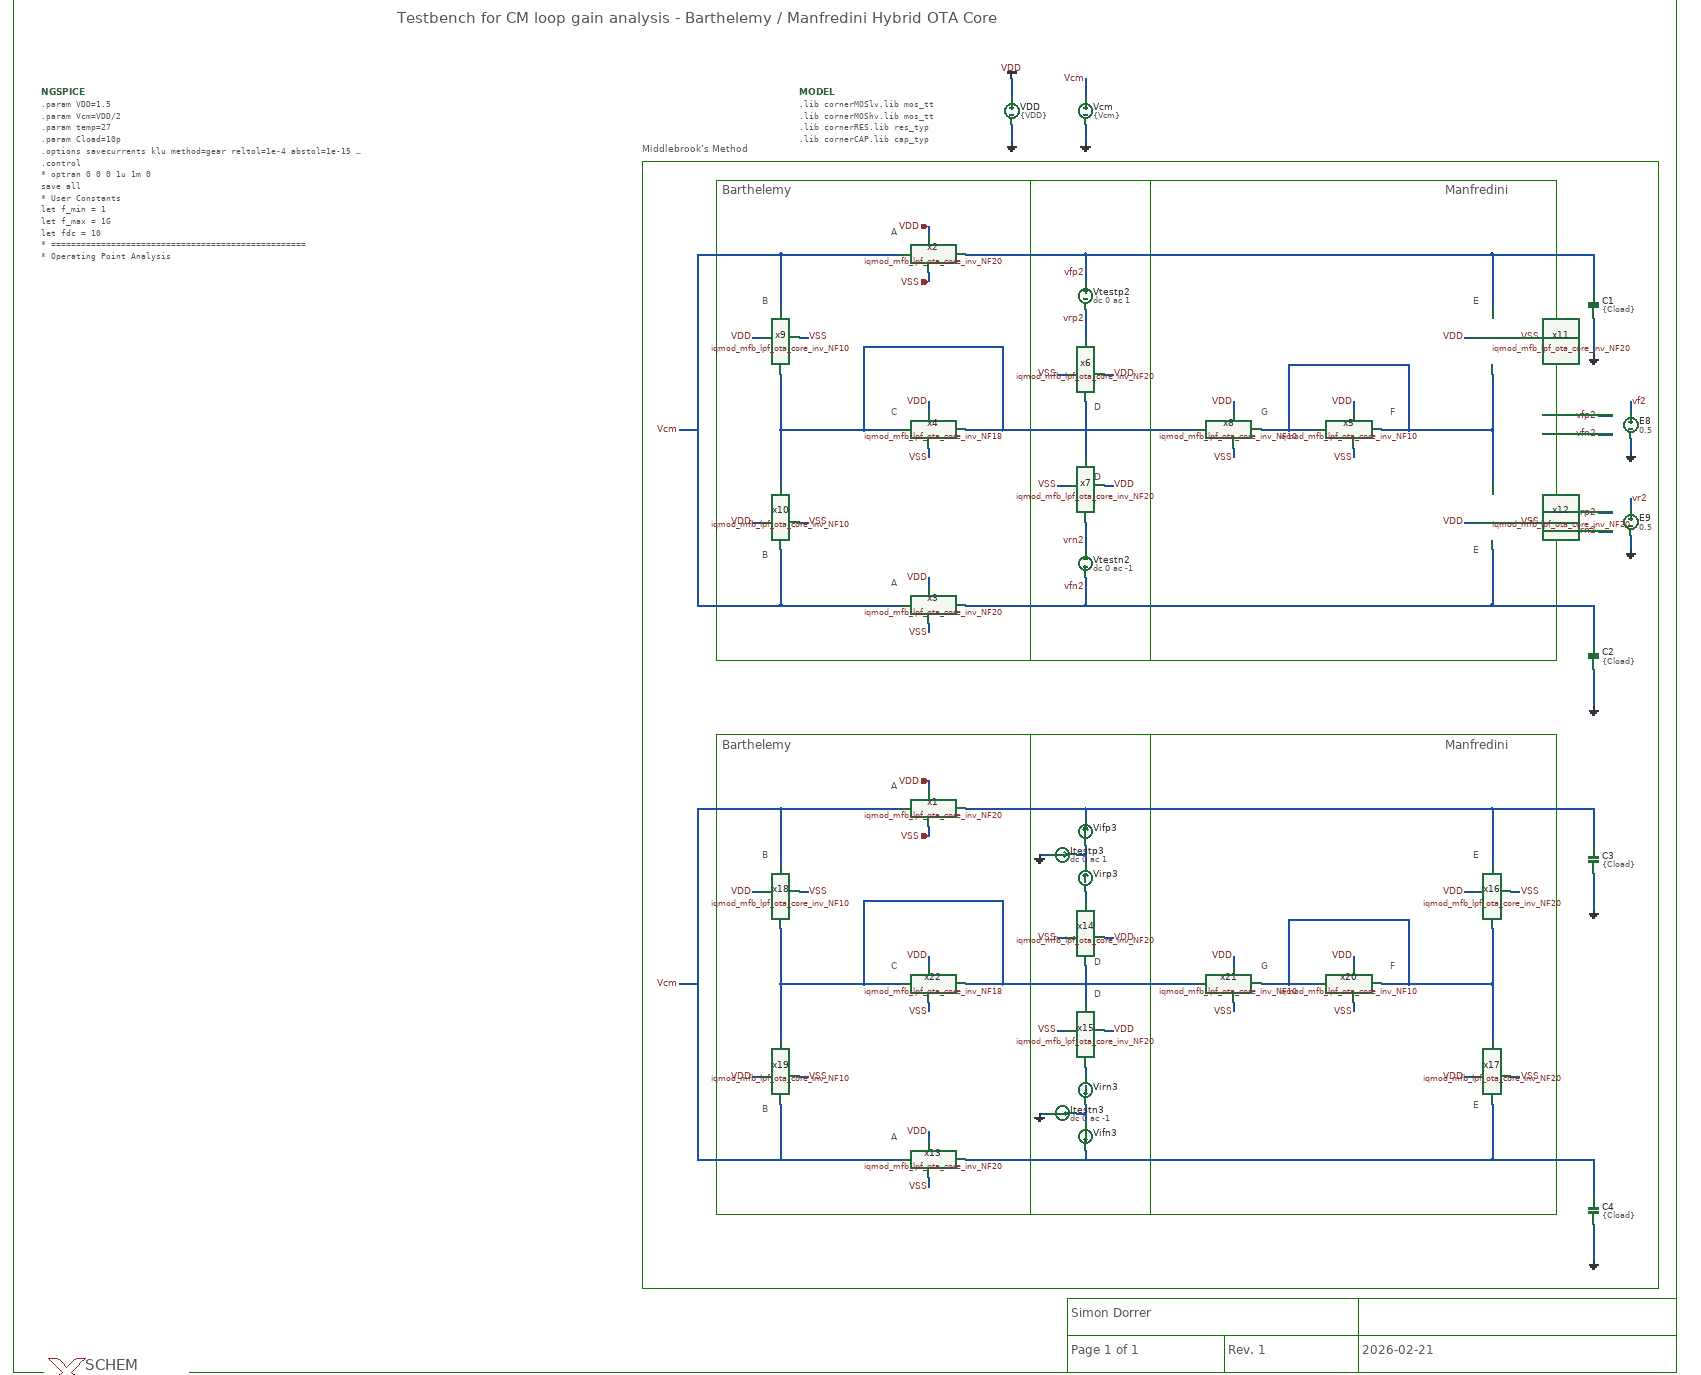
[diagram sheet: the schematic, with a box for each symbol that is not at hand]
v {xschem version=3.4.8RC file_version=1.3}
G {}
K {}
V {}
S {}
F {}
E {}
L 4 0 0 65 0 {}
L 4 2280 -160 2280 0 {}
L 4 2280 -160 3600 -160 {}
L 4 2280 -80 3600 -80 {}
L 4 2910 -80 2910 0 {}
L 4 2910 -160 2910 -80 {}
L 4 2620 -80 2620 0 {}
L 4 380 0 1000 0 {}
L 4 0 -2980 -0 -0 {}
L 4 3600 -2980 3600 0 {}
L 4 1000 0 3600 0 {}
L 4 -0 -2980 3600 -2980 {}
P 4 5 1360 -2620 3560 -2620 3560 -180 1360 -180 1360 -2620 {dash = 8}
P 4 5 1520 -2580 2460 -2580 2460 -1540 1520 -1540 1520 -2580 {dash = 8}
P 4 5 2200 -2580 3340 -2580 3340 -1540 2200 -1540 2200 -2580 {dash = 8}
P 4 5 1520 -1380 2460 -1380 2460 -340 1520 -340 1520 -1380 {dash = 8}
P 4 5 2200 -1380 3340 -1380 3340 -340 2200 -340 2200 -1380 {dash = 8}
P 5 38 140 -15 135 -10 125 0 135 10 147.5 22.5 155 30 147.5 30 140 30 135 30 130 25 125 20 115 10 105 20 100 25 95 30 90 30 82.5 30 75 30 82.5 22.5 95 10 105 0 95 -10 82.5 -22.5 75 -30 82.5 -30 90 -30 95 -30 100 -25 105 -20 115 -10 125 -20 130 -25 135 -30 140 -30 147.5 -30 155 -30 147.5 -22.5 140 -15 {fill=true
bezier=1}
T {Testbench for CM loop gain analysis - Barthelemy / Manfredini Hybrid OTA Core} 830 -2940 0 0 1 1 {}
T {Middlebrook’s Method} 1360 -2660 0 0 0.5 0.5 {}
T {2026-02-21} 2920 -60 0 0 0.8 0.8 {}
T {Simon Dorrer} 2290 -140 0 0 0.8 0.8 {}
T {Page 1 of 1} 2290 -60 0 0 0.8 0.8 {}
T {Rev. 1} 2630 -60 0 0 0.8 0.8 {}
T {SCHEM} 155 -25 0 0 1 1 {}
T {B} 1620 -2330 0 0 0.6 0.6 {}
T {B} 1620 -1780 0 0 0.6 0.6 {}
T {C} 1900 -2090 0 0 0.6 0.6 {}
T {A} 1900 -2480 0 0 0.6 0.6 {}
T {A} 1900 -1720 0 0 0.6 0.6 {}
T {D} 2340 -2100 0 0 0.6 0.6 {}
T {D} 2340 -1950 0 0 0.6 0.6 {}
T {Manfredini} 3100 -2570 0 0 0.8 0.8 {}
T {Barthelemy} 1535 -2570 0 0 0.8 0.8 {}
T {E} 3160 -2330 0 0 0.6 0.6 {}
T {E} 3160 -1790 0 0 0.6 0.6 {}
T {F} 2980 -2090 0 1 0.6 0.6 {}
T {G} 2700 -2090 0 0 0.6 0.6 {}
T {B} 1620 -1130 0 0 0.6 0.6 {}
T {B} 1620 -580 0 0 0.6 0.6 {}
T {C} 1900 -890 0 0 0.6 0.6 {}
T {A} 1900 -1280 0 0 0.6 0.6 {}
T {A} 1900 -520 0 0 0.6 0.6 {}
T {D} 2340 -900 0 0 0.6 0.6 {}
T {D} 2340 -830 0 0 0.6 0.6 {}
T {Manfredini} 3100 -1370 0 0 0.8 0.8 {}
T {Barthelemy} 1535 -1370 0 0 0.8 0.8 {}
T {E} 3160 -1130 0 0 0.6 0.6 {}
T {E} 3160 -590 0 0 0.6 0.6 {}
T {F} 2980 -890 0 1 0.6 0.6 {}
T {G} 2700 -890 0 0 0.6 0.6 {}
N 2160 -2800 2160 -2760 {lab=VDD}
N 2160 -2700 2160 -2660 {lab=GND}
N 3500 -2100 3500 -2080 {
lab=vf2}
N 3430 -2070 3460 -2070 {
lab=vfp2}
N 3430 -2030 3460 -2030 {
lab=vfn2}
N 3500 -2020 3500 -1990 {
lab=GND}
N 3500 -1890 3500 -1870 {
lab=vr2}
N 3430 -1860 3460 -1860 {
lab=vrp2}
N 3430 -1820 3460 -1820 {
lab=vrn2}
N 3500 -1810 3500 -1780 {
lab=GND}
N 2320 -560 2320 -540 {
lab=#net1}
N 2320 -580 2320 -560 {
lab=#net1}
N 2320 -1140 2320 -1120 {
lab=#net2}
N 2320 -1120 2320 -1100 {
lab=#net2}
N 2220 -560 2240 -560 {lab=GND}
N 2300 -560 2320 -560 {lab=#net1}
N 2300 -1120 2320 -1120 {lab=#net2}
N 2220 -1120 2240 -1120 {lab=GND}
N 2320 -2700 2320 -2660 {lab=GND}
N 2320 -2800 2320 -2760 {lab=Vcm}
N 1980 -2480 1980 -2460 {lab=VDD}
N 1980 -2380 1980 -2360 {lab=VSS}
N 1980 -1720 1980 -1700 {lab=VDD}
N 1980 -1620 1980 -1600 {lab=VSS}
N 2360 -1920 2380 -1920 {lab=VDD}
N 2260 -1920 2280 -1920 {lab=VSS}
N 2360 -2160 2380 -2160 {lab=VDD}
N 2260 -2160 2280 -2160 {lab=VSS}
N 1600 -2240 1620 -2240 {lab=VDD}
N 1700 -2240 1720 -2240 {lab=VSS}
N 1600 -1840 1620 -1840 {lab=VDD}
N 1700 -1840 1720 -1840 {lab=VSS}
N 1660 -1660 1920 -1660 {lab=Vcm}
N 1660 -1780 1660 -1660 {lab=Vcm}
N 1660 -2420 1660 -2300 {lab=Vcm}
N 1660 -2420 1920 -2420 {lab=Vcm}
N 1980 -2100 1980 -2080 {lab=VDD}
N 1980 -2000 1980 -1980 {lab=VSS}
N 1840 -2040 1920 -2040 {lab=#net3}
N 2140 -2220 2140 -2040 {lab=#net3}
N 1840 -2220 2140 -2220 {lab=#net3}
N 1840 -2220 1840 -2040 {lab=#net3}
N 2640 -2100 2640 -2080 {lab=VDD}
N 2640 -2000 2640 -1980 {lab=VSS}
N 3140 -2240 3160 -2240 {lab=VDD}
N 3240 -2240 3260 -2240 {lab=VSS}
N 3140 -1840 3160 -1840 {lab=VDD}
N 3240 -1840 3260 -1840 {lab=VSS}
N 2900 -2100 2900 -2080 {lab=VDD}
N 2900 -2000 2900 -1980 {lab=VSS}
N 2760 -2040 2820 -2040 {lab=#net4}
N 2760 -2180 2760 -2040 {lab=#net4}
N 3200 -2420 3200 -2300 {lab=vfp2}
N 3200 -1780 3200 -1660 {lab=vfn2}
N 2060 -2040 2140 -2040 {lab=#net3}
N 2700 -2040 2760 -2040 {lab=#net4}
N 1480 -1660 1660 -1660 {lab=Vcm}
N 1480 -2420 1660 -2420 {lab=Vcm}
N 3200 -1660 3420 -1660 {lab=vfn2}
N 3420 -2420 3420 -2340 {lab=vfp2}
N 3200 -2420 3420 -2420 {lab=vfp2}
N 3420 -2280 3420 -2200 {lab=GND}
N 3420 -1660 3420 -1580 {lab=vfn2}
N 3420 -1520 3420 -1440 {lab=GND}
N 1980 -1280 1980 -1260 {lab=VDD}
N 1980 -1180 1980 -1160 {lab=VSS}
N 1980 -520 1980 -500 {lab=VDD}
N 1980 -420 1980 -400 {lab=VSS}
N 2360 -740 2380 -740 {lab=VDD}
N 2260 -740 2280 -740 {lab=VSS}
N 2360 -940 2380 -940 {lab=VDD}
N 2260 -940 2280 -940 {lab=VSS}
N 1600 -1040 1620 -1040 {lab=VDD}
N 1700 -1040 1720 -1040 {lab=VSS}
N 1600 -640 1620 -640 {lab=VDD}
N 1700 -640 1720 -640 {lab=VSS}
N 1660 -460 1920 -460 {lab=Vcm}
N 1660 -580 1660 -460 {lab=Vcm}
N 1660 -1220 1660 -1100 {lab=Vcm}
N 1660 -1220 1920 -1220 {lab=Vcm}
N 1980 -900 1980 -880 {lab=VDD}
N 1980 -800 1980 -780 {lab=VSS}
N 2140 -1020 2140 -840 {lab=#net5}
N 2640 -900 2640 -880 {lab=VDD}
N 2640 -800 2640 -780 {lab=VSS}
N 3140 -1040 3160 -1040 {lab=VDD}
N 3240 -1040 3260 -1040 {lab=VSS}
N 3140 -640 3160 -640 {lab=VDD}
N 3240 -640 3260 -640 {lab=VSS}
N 2900 -900 2900 -880 {lab=VDD}
N 2900 -800 2900 -780 {lab=VSS}
N 2760 -840 2820 -840 {lab=#net6}
N 2760 -980 2760 -840 {lab=#net6}
N 3200 -1220 3200 -1100 {lab=#net7}
N 3200 -580 3200 -460 {lab=#net8}
N 2060 -840 2140 -840 {lab=#net5}
N 2700 -840 2760 -840 {lab=#net6}
N 1480 -460 1660 -460 {lab=Vcm}
N 1480 -1220 1660 -1220 {lab=Vcm}
N 3200 -460 3420 -460 {lab=#net8}
N 3420 -1220 3420 -1140 {lab=#net7}
N 3200 -1220 3420 -1220 {lab=#net7}
N 3420 -1080 3420 -1000 {lab=GND}
N 3420 -460 3420 -380 {lab=#net8}
N 3420 -320 3420 -240 {lab=GND}
N 2320 -2040 2560 -2040 {lab=#net3}
N 2320 -2420 2320 -2360 {lab=vfp2}
N 2140 -2040 2320 -2040 {lab=#net3}
N 3200 -2040 3200 -1920 {lab=#net4}
N 2320 -2300 2320 -2240 {lab=vrp2}
N 1660 -2040 1660 -1920 {lab=#net3}
N 2320 -2420 3200 -2420 {lab=vfp2}
N 2320 -1660 3200 -1660 {lab=vfn2}
N 2320 -840 2560 -840 {lab=#net5}
N 2320 -460 3200 -460 {lab=#net8}
N 1660 -840 1660 -720 {lab=#net5}
N 3200 -840 3200 -720 {lab=#net6}
N 2320 -480 2320 -460 {lab=#net8}
N 1660 -2040 1840 -2040 {lab=#net3}
N 1660 -2160 1660 -2040 {lab=#net3}
N 2060 -2420 2320 -2420 {lab=vfp2}
N 2320 -2100 2320 -2040 {lab=#net3}
N 2320 -2040 2320 -1980 {lab=#net3}
N 2320 -1840 2320 -1780 {lab=vrn2}
N 2320 -1720 2320 -1660 {lab=vfn2}
N 2060 -1660 2320 -1660 {lab=vfn2}
N 2960 -2040 3020 -2040 {lab=#net4}
N 2760 -2180 3020 -2180 {lab=#net4}
N 3020 -2180 3020 -2040 {lab=#net4}
N 3020 -2040 3200 -2040 {lab=#net4}
N 3200 -2160 3200 -2040 {lab=#net4}
N 2140 -840 2320 -840 {lab=#net5}
N 2960 -840 3020 -840 {lab=#net6}
N 3020 -980 3020 -840 {lab=#net6}
N 2760 -980 3020 -980 {lab=#net6}
N 3020 -840 3200 -840 {lab=#net6}
N 3200 -960 3200 -840 {lab=#net6}
N 1840 -840 1920 -840 {lab=#net5}
N 1840 -1020 1840 -840 {lab=#net5}
N 1840 -1020 2140 -1020 {lab=#net5}
N 1660 -840 1840 -840 {lab=#net5}
N 1660 -960 1660 -840 {lab=#net5}
N 2320 -1220 3200 -1220 {lab=#net7}
N 2320 -880 2320 -840 {lab=#net5}
N 2320 -1040 2320 -1020 {lab=#net9}
N 2320 -1220 2320 -1200 {lab=#net7}
N 2060 -1220 2320 -1220 {lab=#net7}
N 2060 -460 2320 -460 {lab=#net8}
N 2320 -840 2320 -800 {lab=#net5}
N 2320 -660 2320 -640 {lab=#net10}
N 1480 -2040 1480 -1660 {lab=Vcm}
N 1440 -2040 1480 -2040 {lab=Vcm}
N 1480 -2420 1480 -2040 {lab=Vcm}
N 1480 -840 1480 -460 {lab=Vcm}
N 1440 -840 1480 -840 {lab=Vcm}
N 1480 -1220 1480 -840 {lab=Vcm}
C {devices/code_shown.sym} 60 -2770 0 0 {name=NGSPICE
only_toplevel=true 
value="
.param VDD=1.5
.param Vcm=VDD/2
.param temp=27
.param Cload=10p
.options savecurrents klu method=gear reltol=1e-4 abstol=1e-15 gmin=1e-15
.control

* optran 0 0 0 1u 1m 0

save all

* User Constants
let f_min = 1
let f_max = 1G
let fdc = 10
* ===================================================

* Operating Point Analysis
op
remzerovec
write iqmod_mfb_lpf_ota_core_tb_cm_loopgain.raw
set appendwrite
* ===================================================

* AC Analysis
ac dec 101 $&const.f_min $&const.f_max
remzerovec
write iqmod_mfb_lpf_ota_core_tb_cm_loopgain.raw
set appendwrite
* ===================================================

* Middlebrook's method
let Tv=-v(vr2)/v(vf2)
let Ti=-(i(Virp3) - i(Virn3))/(i(Vifp3) - i(Vifn3))
let Tmb =(Tv * Ti - 1)/(Tv + Ti + 2)

let Tmb_dB = vdb(Tmb)
let Tmb_arg = 180/PI*cphase(Tmb)

* DC loop gain	
meas ac Tmbdc_dB find Tmb_dB when frequency = fdc
print Tmbdc_dB

* Phase margin
meas ac fug find frequency when Tmb_dB=0
meas ac pm find Tmb_arg when frequency=fug
let pm = 180-abs(pm)
* let pm = abs(pm)
print pm
	
* Plotting
plot Tmb_dB Tmb_arg title 'Bode Plot (Middlebrook)' ylabel 'Magnitude (dB), Phase (Deg)'

let Tmb_re = real(Tmb)
let Tmb_im = imag(Tmb)	
plot Tmb_im vs Tmb_re retraceplot title 'Nyquist Plot (Middlebrook)' ylabel 'Imaginary Part' xlabel 'Real Part' 
* ===================================================

* Write Data
unset appendwrite
set wr_vecnames
set wr_singlescale
wrdata $PROJECT_PATH/python/plot_simulations/data/iqmod_mfb_lpf_ota_core_tb_cm_loopgain.txt v(Tmb_dB) v(Tmb_arg) 
* ===================================================

*quit
.endc
"}
C {devices/vsource.sym} 2160 -2730 0 0 {name=VDD value=\{VDD\}}
C {devices/gnd.sym} 2160 -2660 0 0 {name=l3 lab=GND}
C {devices/launcher.sym} 1420 -2780 0 0 {name=h2
descr="Simulate" 
tclcommand="xschem save; xschem netlist; xschem simulate"
}
C {devices/launcher.sym} 1420 -2720 0 0 {name=h3
descr="Annotate OP" 
tclcommand="set show_hidden_texts 1; xschem annotate_op"
}
C {vdd.sym} 2160 -2800 0 0 {name=l7 lab=VDD}
C {devices/capa.sym} 3420 -1550 0 0 {name=C2
m=1
value=\{Cload\}
footprint=1206
device="ceramic capacitor"}
C {devices/capa.sym} 3420 -2310 0 0 {name=C1
m=1
value=\{Cload\}
footprint=1206
device="ceramic capacitor"}
C {devices/gnd.sym} 3420 -2200 0 0 {name=l36 lab=GND}
C {devices/lab_pin.sym} 1440 -2040 0 0 {name=l65 sig_type=std_logic lab=Vcm}
C {devices/lab_pin.sym} 3500 -2100 0 1 {name=l48 sig_type=std_logic lab=vf2}
C {devices/vcvs.sym} 3500 -2050 0 0 {name=E8 value=0.5}
C {devices/gnd.sym} 3500 -1990 0 0 {name=l33 lab=GND}
C {devices/lab_pin.sym} 3430 -2030 2 1 {name=l45 sig_type=std_logic lab=vfn2
}
C {devices/lab_pin.sym} 3430 -2070 0 0 {name=l46 sig_type=std_logic lab=vfp2

}
C {devices/lab_pin.sym} 3500 -1890 0 1 {name=l47 sig_type=std_logic lab=vr2}
C {devices/vcvs.sym} 3500 -1840 0 0 {name=E9 value=0.5}
C {devices/gnd.sym} 3500 -1780 0 0 {name=l53 lab=GND}
C {devices/lab_pin.sym} 3430 -1820 2 1 {name=l54 sig_type=std_logic lab=vrn2
}
C {devices/lab_pin.sym} 3430 -1860 0 0 {name=l61 sig_type=std_logic lab=vrp2

}
C {devices/vsource.sym} 2320 -2330 0 1 {name=Vtestp2 value="dc 0 ac 1"}
C {lab_wire.sym} 2320 -2380 0 0 {name=p9 sig_type=std_logic lab=vfp2}
C {lab_wire.sym} 2320 -2280 0 0 {name=p13 sig_type=std_logic lab=vrp2}
C {devices/vsource.sym} 2320 -1750 2 0 {name=Vtestn2 value="dc 0 ac -1"}
C {lab_wire.sym} 2320 -1700 0 0 {name=p10 sig_type=std_logic lab=vfn2}
C {lab_wire.sym} 2320 -1800 2 1 {name=p11 sig_type=std_logic lab=vrn2}
C {ammeter.sym} 2320 -1070 2 1 {name=Virp3 savecurrent=true spice_ignore=0}
C {ammeter.sym} 2320 -1170 2 1 {name=Vifp3 savecurrent=true spice_ignore=0}
C {isource.sym} 2270 -560 3 1 {name=Itestn3 value="dc 0 ac -1"}
C {devices/gnd.sym} 2220 -560 1 0 {name=l62 lab=GND}
C {ammeter.sym} 2320 -610 0 0 {name=Virn3 savecurrent=true spice_ignore=0}
C {ammeter.sym} 2320 -510 0 0 {name=Vifn3 savecurrent=true spice_ignore=0}
C {isource.sym} 2270 -1120 3 0 {name=Itestp3 value="dc 0 ac 1"}
C {devices/gnd.sym} 2220 -1120 1 0 {name=l63 lab=GND}
C {devices/vsource.sym} 2320 -2730 0 0 {name=Vcm value=\{Vcm\}
}
C {devices/lab_pin.sym} 2320 -2800 1 0 {name=l38 sig_type=std_logic lab=Vcm}
C {devices/gnd.sym} 2320 -2660 0 0 {name=l40 lab=GND}
C {devices/code_shown.sym} 1700 -2770 0 0 {name=MODEL only_toplevel=true
format="tcleval( @value )"
value="
.lib cornerMOSlv.lib mos_tt
.lib cornerMOShv.lib mos_tt
.lib cornerRES.lib res_typ
.lib cornerCAP.lib cap_typ
"}
C {lab_pin.sym} 1980 -1720 3 1 {name=p7 sig_type=std_logic lab=VDD}
C {lab_pin.sym} 1980 -1600 1 1 {name=p8 sig_type=std_logic lab=VSS}
C {devices/iopin.sym} 1980 -2480 3 0 {name=p23 lab=VDD}
C {devices/iopin.sym} 1980 -2360 1 0 {name=p24 lab=VSS}
C {lab_pin.sym} 2380 -1920 0 1 {name=p12 sig_type=std_logic lab=VDD}
C {lab_pin.sym} 2260 -1920 2 1 {name=p14 sig_type=std_logic lab=VSS}
C {lab_pin.sym} 2380 -2160 2 0 {name=p18 sig_type=std_logic lab=VDD}
C {lab_pin.sym} 2260 -2160 0 0 {name=p19 sig_type=std_logic lab=VSS}
C {lab_pin.sym} 1600 -2240 0 0 {name=p21 sig_type=std_logic lab=VDD}
C {lab_pin.sym} 1720 -2240 2 0 {name=p26 sig_type=std_logic lab=VSS}
C {lab_pin.sym} 1600 -1840 2 1 {name=p28 sig_type=std_logic lab=VDD}
C {lab_pin.sym} 1720 -1840 0 1 {name=p29 sig_type=std_logic lab=VSS}
C {lab_pin.sym} 1980 -2100 3 1 {name=p15 sig_type=std_logic lab=VDD}
C {lab_pin.sym} 1980 -1980 1 1 {name=p16 sig_type=std_logic lab=VSS}
C {lab_pin.sym} 2640 -2100 1 0 {name=p34 sig_type=std_logic lab=VDD
}
C {lab_pin.sym} 2640 -1980 3 0 {name=p35 sig_type=std_logic lab=VSS
}
C {lab_pin.sym} 3140 -2240 0 0 {name=p37 sig_type=std_logic lab=VDD}
C {lab_pin.sym} 3260 -2240 2 0 {name=p38 sig_type=std_logic lab=VSS}
C {lab_pin.sym} 3140 -1840 2 1 {name=p40 sig_type=std_logic lab=VDD}
C {lab_pin.sym} 3260 -1840 0 1 {name=p41 sig_type=std_logic lab=VSS}
C {lab_pin.sym} 2900 -2100 1 0 {name=p43 sig_type=std_logic lab=VDD}
C {lab_pin.sym} 2900 -1980 3 0 {name=p44 sig_type=std_logic lab=VSS}
C {iqmod_mfb_lpf_ota_core_inv_NF20.sym} 1980 -2420 0 0 {name=x2}
C {iqmod_mfb_lpf_ota_core_inv_NF20.sym} 1980 -1660 0 0 {name=x3}
C {iqmod_mfb_lpf_ota_core_inv_NF20.sym} 2320 -2160 1 1 {name=x6}
C {iqmod_mfb_lpf_ota_core_inv_NF20.sym} 2320 -1920 1 0 {name=x7}
C {iqmod_mfb_lpf_ota_core_inv_NF20.sym} 3200 -2240 3 1 {name=x11}
C {iqmod_mfb_lpf_ota_core_inv_NF20.sym} 3200 -1840 3 0 {name=x12}
C {iqmod_mfb_lpf_ota_core_inv_NF10.sym} 1660 -2240 3 1 {name=x9}
C {iqmod_mfb_lpf_ota_core_inv_NF10.sym} 1660 -1840 3 0 {name=x10}
C {iqmod_mfb_lpf_ota_core_inv_NF10.sym} 2900 -2040 0 1 {name=x5}
C {iqmod_mfb_lpf_ota_core_inv_NF10.sym} 2640 -2040 0 1 {name=x8}
C {devices/gnd.sym} 3420 -1440 0 0 {name=l2 lab=GND}
C {devices/capa.sym} 3420 -350 0 0 {name=C4
m=1
value=\{Cload\}
footprint=1206
device="ceramic capacitor"}
C {devices/capa.sym} 3420 -1110 0 0 {name=C3
m=1
value=\{Cload\}
footprint=1206
device="ceramic capacitor"}
C {devices/gnd.sym} 3420 -1000 0 0 {name=l4 lab=GND}
C {devices/lab_pin.sym} 1440 -840 0 0 {name=l5 sig_type=std_logic lab=Vcm}
C {lab_pin.sym} 1980 -520 3 1 {name=p17 sig_type=std_logic lab=VDD}
C {lab_pin.sym} 1980 -400 1 1 {name=p20 sig_type=std_logic lab=VSS}
C {devices/iopin.sym} 1980 -1280 3 0 {name=p22 lab=VDD}
C {devices/iopin.sym} 1980 -1160 1 0 {name=p25 lab=VSS}
C {lab_pin.sym} 2380 -740 0 1 {name=p27 sig_type=std_logic lab=VDD}
C {lab_pin.sym} 2260 -740 2 1 {name=p32 sig_type=std_logic lab=VSS}
C {lab_pin.sym} 2380 -940 2 0 {name=p33 sig_type=std_logic lab=VDD}
C {lab_pin.sym} 2260 -940 0 0 {name=p36 sig_type=std_logic lab=VSS}
C {lab_pin.sym} 1600 -1040 0 0 {name=p39 sig_type=std_logic lab=VDD}
C {lab_pin.sym} 1720 -1040 2 0 {name=p42 sig_type=std_logic lab=VSS}
C {lab_pin.sym} 1600 -640 2 1 {name=p45 sig_type=std_logic lab=VDD}
C {lab_pin.sym} 1720 -640 0 1 {name=p46 sig_type=std_logic lab=VSS}
C {lab_pin.sym} 1980 -900 3 1 {name=p47 sig_type=std_logic lab=VDD}
C {lab_pin.sym} 1980 -780 1 1 {name=p48 sig_type=std_logic lab=VSS}
C {lab_pin.sym} 2640 -900 1 0 {name=p49 sig_type=std_logic lab=VDD
}
C {lab_pin.sym} 2640 -780 3 0 {name=p50 sig_type=std_logic lab=VSS
}
C {lab_pin.sym} 3140 -1040 0 0 {name=p51 sig_type=std_logic lab=VDD}
C {lab_pin.sym} 3260 -1040 2 0 {name=p52 sig_type=std_logic lab=VSS}
C {lab_pin.sym} 3140 -640 2 1 {name=p53 sig_type=std_logic lab=VDD}
C {lab_pin.sym} 3260 -640 0 1 {name=p54 sig_type=std_logic lab=VSS}
C {lab_pin.sym} 2900 -900 1 0 {name=p55 sig_type=std_logic lab=VDD}
C {lab_pin.sym} 2900 -780 3 0 {name=p56 sig_type=std_logic lab=VSS}
C {iqmod_mfb_lpf_ota_core_inv_NF20.sym} 1980 -1220 0 0 {name=x1}
C {iqmod_mfb_lpf_ota_core_inv_NF20.sym} 1980 -460 0 0 {name=x13}
C {iqmod_mfb_lpf_ota_core_inv_NF20.sym} 2320 -940 1 1 {name=x14}
C {iqmod_mfb_lpf_ota_core_inv_NF20.sym} 2320 -740 1 0 {name=x15}
C {iqmod_mfb_lpf_ota_core_inv_NF20.sym} 3200 -1040 3 1 {name=x16}
C {iqmod_mfb_lpf_ota_core_inv_NF20.sym} 3200 -640 3 0 {name=x17}
C {iqmod_mfb_lpf_ota_core_inv_NF10.sym} 1660 -1040 3 1 {name=x18}
C {iqmod_mfb_lpf_ota_core_inv_NF10.sym} 1660 -640 3 0 {name=x19}
C {iqmod_mfb_lpf_ota_core_inv_NF10.sym} 2900 -840 0 1 {name=x20}
C {iqmod_mfb_lpf_ota_core_inv_NF10.sym} 2640 -840 0 1 {name=x21}
C {devices/gnd.sym} 3420 -240 0 0 {name=l6 lab=GND}
C {archive/iqmod_mfb_lpf_ota_core_inv_NF18.sym} 1980 -2040 0 0 {name=x4}
C {archive/iqmod_mfb_lpf_ota_core_inv_NF18.sym} 1980 -840 0 0 {name=x22}
